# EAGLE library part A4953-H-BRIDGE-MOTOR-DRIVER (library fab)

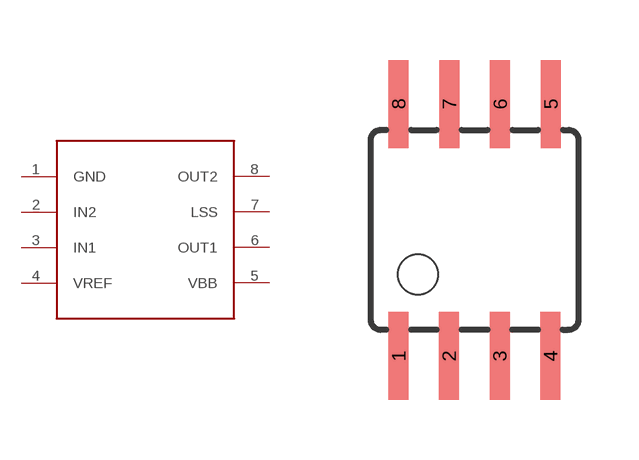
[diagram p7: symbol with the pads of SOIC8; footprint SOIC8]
Designator prefix -

## A4953-H-BRIDGE-MOTOR-DRIVER  [SOIC8]
1  GND
2  IN2
3  IN1
4  VREF
5  VBB
6  OUT1
7  LSS
8  OUT2

## Footprint SOIC8 (pad centres in mm)
Wide Plastic Gull Wing Small Outline Package
smd 0.5 x 2.2: 1 -1.905,-3.154; 2 -0.645,-3.154; 3 0.625,-3.154; 4 1.895,-3.154; 5 1.905,3.154; 6 0.635,3.154; 7 -0.635,3.154; 8 -1.905,3.154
